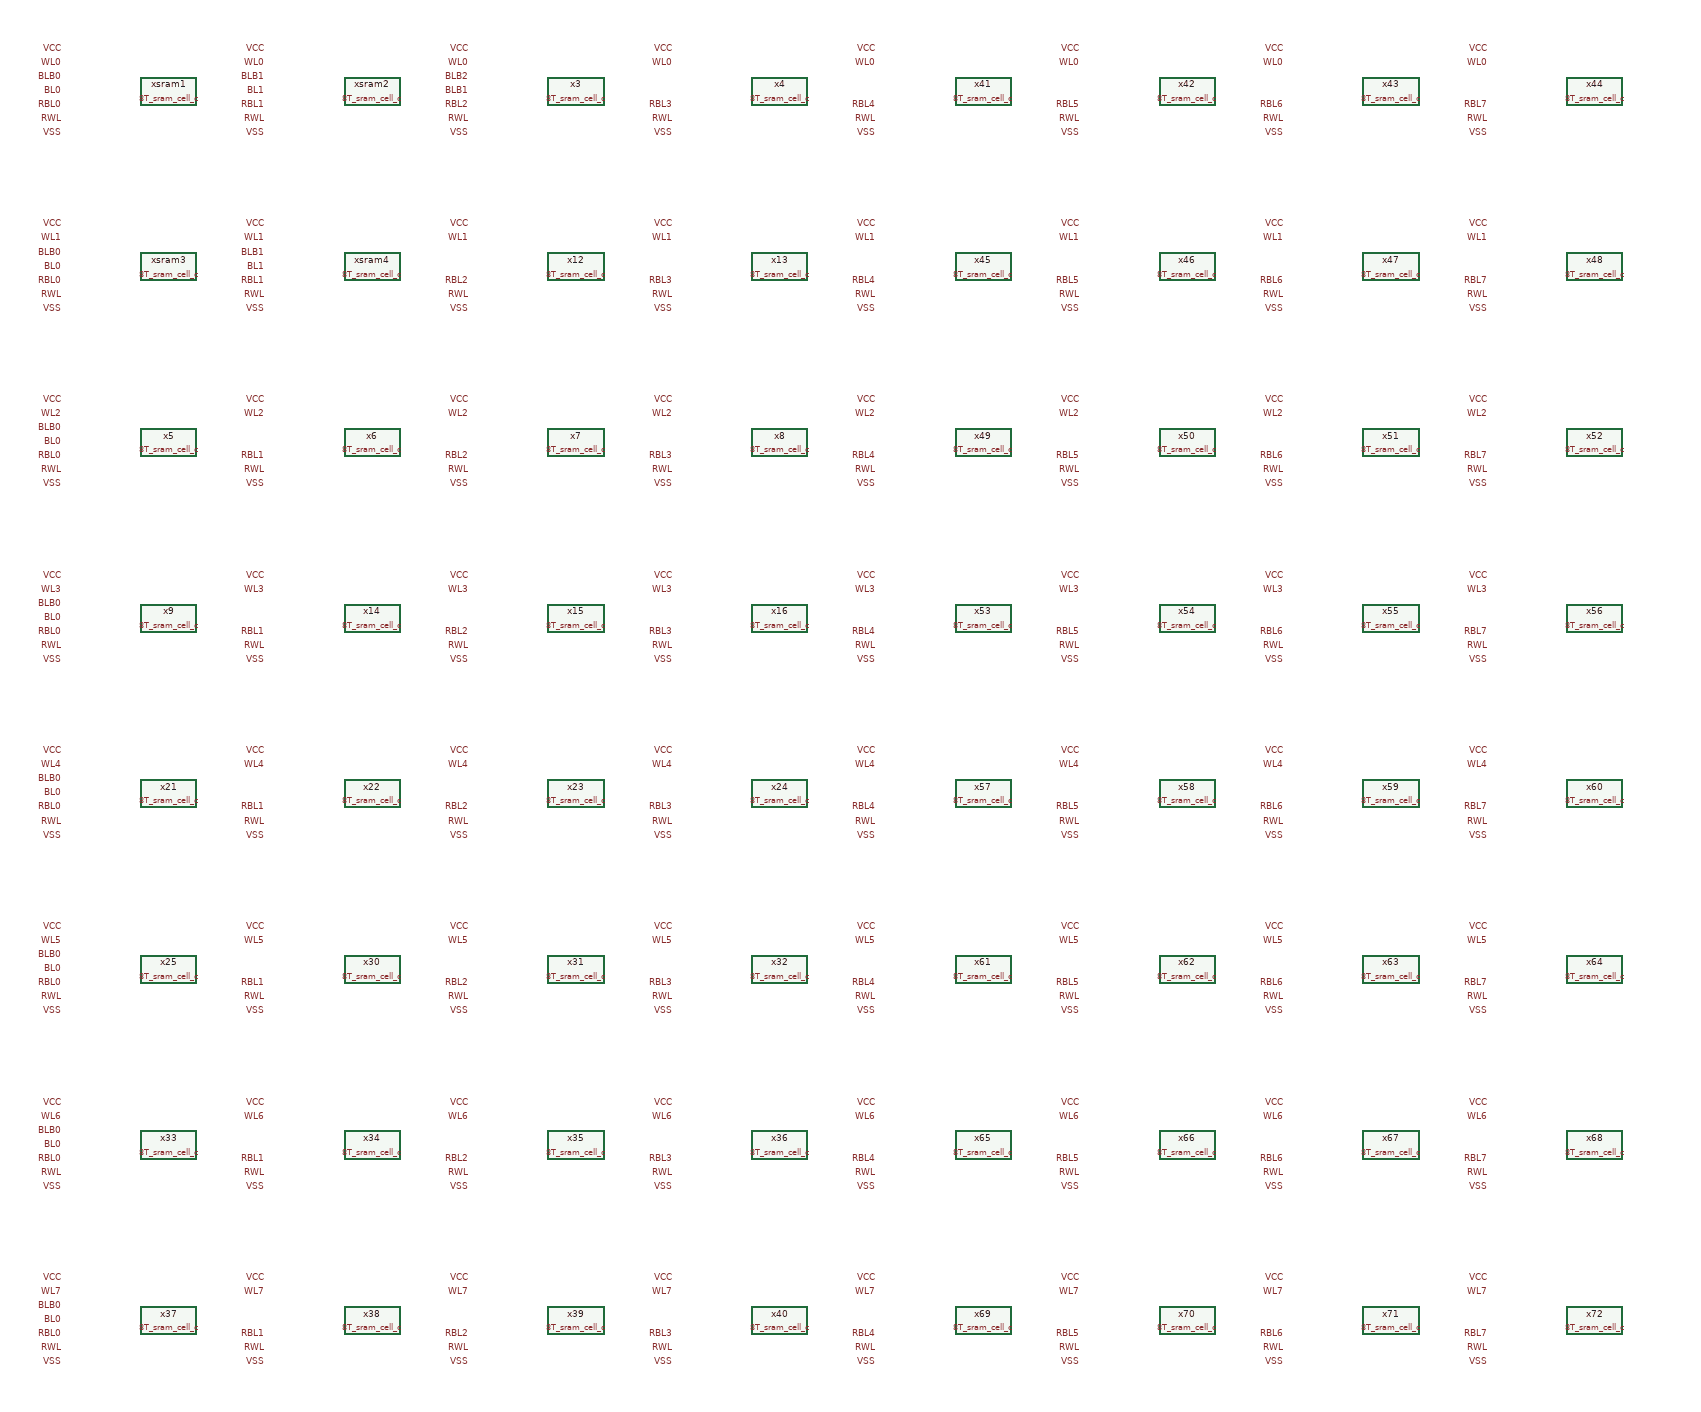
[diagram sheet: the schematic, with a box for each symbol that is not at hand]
v {xschem version=3.4.8RC file_version=1.3}
G {}
K {}
V {}
S {}
F {}
E {}
C {8T_sram_cell_c.sym} 1090 -2060 0 1 {name=xsram1}
C {lab_pin.sym} 940 -2120 0 0 {name=p51 sig_type=std_logic lab=VCC}
C {lab_pin.sym} 940 -2100 0 0 {name=p1 sig_type=std_logic lab=WL0}
C {lab_pin.sym} 940 -2080 0 0 {name=p3 sig_type=std_logic lab=BLB0}
C {lab_pin.sym} 940 -2060 0 0 {name=p4 sig_type=std_logic lab=BL0}
C {lab_pin.sym} 940 -2040 0 0 {name=p112 sig_type=std_logic lab=RBL0}
C {lab_pin.sym} 940 -2020 0 0 {name=p87 sig_type=std_logic lab=RWL}
C {lab_pin.sym} 940 -2000 0 0 {name=p43 sig_type=std_logic lab=VSS}
C {8T_sram_cell_c.sym} 1380 -2060 0 1 {name=xsram2}
C {lab_pin.sym} 1230 -2120 0 0 {name=p6 sig_type=std_logic lab=VCC}
C {lab_pin.sym} 1230 -2100 0 0 {name=p2 sig_type=std_logic lab=WL0}
C {lab_pin.sym} 1230 -2080 0 0 {name=p76 sig_type=std_logic lab=BLB1}
C {lab_pin.sym} 1230 -2060 0 0 {name=p77 sig_type=std_logic lab=BL1}
C {lab_pin.sym} 1230 -2040 0 0 {name=p105 sig_type=std_logic lab=RBL1}
C {lab_pin.sym} 1230 -2020 0 0 {name=p15 sig_type=std_logic lab=RWL}
C {lab_pin.sym} 1230 -2000 0 0 {name=p5 sig_type=std_logic lab=VSS}
C {8T_sram_cell_c.sym} 1090 -1810 0 1 {name=xsram3}
C {lab_pin.sym} 940 -1870 0 0 {name=p62 sig_type=std_logic lab=VCC}
C {lab_pin.sym} 940 -1850 0 0 {name=p107 sig_type=std_logic lab=WL1}
C {lab_pin.sym} 940 -1830 0 0 {name=p7 sig_type=std_logic lab=BLB0}
C {lab_pin.sym} 940 -1810 0 0 {name=p8 sig_type=std_logic lab=BL0}
C {lab_pin.sym} 940 -1790 0 0 {name=p50 sig_type=std_logic lab=RBL0}
C {lab_pin.sym} 940 -1770 0 0 {name=p10 sig_type=std_logic lab=RWL}
C {lab_pin.sym} 940 -1750 0 0 {name=p9 sig_type=std_logic lab=VSS}
C {8T_sram_cell_c.sym} 1380 -1810 0 1 {name=xsram4}
C {lab_pin.sym} 1230 -1870 0 0 {name=p63 sig_type=std_logic lab=VCC}
C {lab_pin.sym} 1230 -1850 0 0 {name=p108 sig_type=std_logic lab=WL1}
C {lab_pin.sym} 1230 -1830 0 0 {name=p80 sig_type=std_logic lab=BLB1}
C {lab_pin.sym} 1230 -1810 0 0 {name=p81 sig_type=std_logic lab=BL1}
C {lab_pin.sym} 1230 -1790 0 0 {name=p46 sig_type=std_logic lab=RBL1}
C {lab_pin.sym} 1230 -1770 0 0 {name=p13 sig_type=std_logic lab=RWL}
C {lab_pin.sym} 1230 -1750 0 0 {name=p12 sig_type=std_logic lab=VSS}


C {lab_pin.sym} 1520 -2100 0 0 {name=p28 sig_type=std_logic lab=WL0}
C {lab_pin.sym} 1520 -2000 0 0 {name=p31 sig_type=std_logic lab=VSS}
C {lab_pin.sym} 1520 -2120 0 0 {name=p32 sig_type=std_logic lab=VCC}
C {lab_pin.sym} 1520 -2020 0 0 {name=p33 sig_type=std_logic lab=RWL}
C {lab_pin.sym} 1810 -2100 0 0 {name=p36 sig_type=std_logic lab=WL0}
C {lab_pin.sym} 1810 -2000 0 0 {name=p39 sig_type=std_logic lab=VSS}
C {lab_pin.sym} 1810 -2120 0 0 {name=p40 sig_type=std_logic lab=VCC}
C {8T_sram_cell_c.sym} 1670 -2060 0 1 {name=x3}
C {lab_pin.sym} 1810 -2020 0 0 {name=p41 sig_type=std_logic lab=RWL}
C {8T_sram_cell_c.sym} 1960 -2060 0 1 {name=x4}
C {lab_pin.sym} 1810 -2040 0 0 {name=p52 sig_type=std_logic lab=RBL3}
C {lab_pin.sym} 1520 -2040 0 0 {name=p88 sig_type=std_logic lab=RBL2}





C {lab_pin.sym} 1520 -1750 0 0 {name=p19 sig_type=std_logic lab=VSS}

C {lab_pin.sym} 1520 -1770 0 0 {name=p20 sig_type=std_logic lab=RWL}
C {lab_pin.sym} 1810 -1750 0 0 {name=p22 sig_type=std_logic lab=VSS}
C {8T_sram_cell_c.sym} 1670 -1810 0 1 {name=x12}
C {lab_pin.sym} 1810 -1770 0 0 {name=p23 sig_type=std_logic lab=RWL}
C {8T_sram_cell_c.sym} 1960 -1810 0 1 {name=x13}


C {lab_pin.sym} 1520 -1870 0 0 {name=p64 sig_type=std_logic lab=VCC}
C {lab_pin.sym} 1810 -1870 0 0 {name=p65 sig_type=std_logic lab=VCC}

C {lab_pin.sym} 1520 -1850 0 0 {name=p113 sig_type=std_logic lab=WL1}
C {lab_pin.sym} 1810 -1850 0 0 {name=p114 sig_type=std_logic lab=WL1}
C {lab_pin.sym} 1810 -1790 0 0 {name=p29 sig_type=std_logic lab=RBL3}
C {lab_pin.sym} 1520 -1790 0 0 {name=p37 sig_type=std_logic lab=RBL2}


C {lab_pin.sym} 940 -1500 0 0 {name=p11 sig_type=std_logic lab=VSS}
C {lab_pin.sym} 940 -1520 0 0 {name=p14 sig_type=std_logic lab=RWL}
C {lab_pin.sym} 1230 -1500 0 0 {name=p16 sig_type=std_logic lab=VSS}
C {8T_sram_cell_c.sym} 1090 -1560 0 1 {name=x5}
C {lab_pin.sym} 1230 -1520 0 0 {name=p21 sig_type=std_logic lab=RWL}
C {lab_pin.sym} 1520 -1500 0 0 {name=p24 sig_type=std_logic lab=VSS}
C {8T_sram_cell_c.sym} 1380 -1560 0 1 {name=x6}
C {lab_pin.sym} 1520 -1520 0 0 {name=p25 sig_type=std_logic lab=RWL}
C {lab_pin.sym} 1810 -1500 0 0 {name=p27 sig_type=std_logic lab=VSS}
C {8T_sram_cell_c.sym} 1670 -1560 0 1 {name=x7}
C {lab_pin.sym} 1810 -1520 0 0 {name=p30 sig_type=std_logic lab=RWL}
C {8T_sram_cell_c.sym} 1960 -1560 0 1 {name=x8}
C {lab_pin.sym} 940 -1620 0 0 {name=p34 sig_type=std_logic lab=VCC}
C {lab_pin.sym} 1230 -1620 0 0 {name=p35 sig_type=std_logic lab=VCC}
C {lab_pin.sym} 1520 -1620 0 0 {name=p38 sig_type=std_logic lab=VCC}
C {lab_pin.sym} 1810 -1620 0 0 {name=p42 sig_type=std_logic lab=VCC}
C {lab_pin.sym} 940 -1600 0 0 {name=p44 sig_type=std_logic lab=WL2}
C {lab_pin.sym} 1230 -1600 0 0 {name=p45 sig_type=std_logic lab=WL2}
C {lab_pin.sym} 1520 -1600 0 0 {name=p47 sig_type=std_logic lab=WL2}
C {lab_pin.sym} 1810 -1600 0 0 {name=p48 sig_type=std_logic lab=WL2}
C {lab_pin.sym} 1810 -1540 0 0 {name=p49 sig_type=std_logic lab=RBL3}
C {lab_pin.sym} 1520 -1540 0 0 {name=p53 sig_type=std_logic lab=RBL2}
C {lab_pin.sym} 1230 -1540 0 0 {name=p54 sig_type=std_logic lab=RBL1}
C {lab_pin.sym} 940 -1540 0 0 {name=p55 sig_type=std_logic lab=RBL0}
C {lab_pin.sym} 940 -1250 0 0 {name=p56 sig_type=std_logic lab=VSS}
C {lab_pin.sym} 940 -1270 0 0 {name=p57 sig_type=std_logic lab=RWL}
C {lab_pin.sym} 1230 -1250 0 0 {name=p58 sig_type=std_logic lab=VSS}
C {8T_sram_cell_c.sym} 1090 -1310 0 1 {name=x9}
C {lab_pin.sym} 1230 -1270 0 0 {name=p61 sig_type=std_logic lab=RWL}
C {lab_pin.sym} 1520 -1250 0 0 {name=p66 sig_type=std_logic lab=VSS}
C {8T_sram_cell_c.sym} 1380 -1310 0 1 {name=x14}
C {lab_pin.sym} 1520 -1270 0 0 {name=p67 sig_type=std_logic lab=RWL}
C {lab_pin.sym} 1810 -1250 0 0 {name=p68 sig_type=std_logic lab=VSS}
C {8T_sram_cell_c.sym} 1670 -1310 0 1 {name=x15}
C {lab_pin.sym} 1810 -1270 0 0 {name=p94 sig_type=std_logic lab=RWL}
C {8T_sram_cell_c.sym} 1960 -1310 0 1 {name=x16}
C {lab_pin.sym} 940 -1370 0 0 {name=p97 sig_type=std_logic lab=VCC}
C {lab_pin.sym} 1230 -1370 0 0 {name=p98 sig_type=std_logic lab=VCC}
C {lab_pin.sym} 1520 -1370 0 0 {name=p100 sig_type=std_logic lab=VCC}
C {lab_pin.sym} 1810 -1370 0 0 {name=p101 sig_type=std_logic lab=VCC}
C {lab_pin.sym} 940 -1350 0 0 {name=p102 sig_type=std_logic lab=WL3}
C {lab_pin.sym} 1230 -1350 0 0 {name=p103 sig_type=std_logic lab=WL3}
C {lab_pin.sym} 1520 -1350 0 0 {name=p104 sig_type=std_logic lab=WL3}
C {lab_pin.sym} 1810 -1350 0 0 {name=p106 sig_type=std_logic lab=WL3}
C {lab_pin.sym} 1810 -1290 0 0 {name=p109 sig_type=std_logic lab=RBL3}
C {lab_pin.sym} 1520 -1290 0 0 {name=p110 sig_type=std_logic lab=RBL2}
C {lab_pin.sym} 1230 -1290 0 0 {name=p111 sig_type=std_logic lab=RBL1}
C {lab_pin.sym} 940 -1290 0 0 {name=p115 sig_type=std_logic lab=RBL0}
C {lab_pin.sym} 940 -1000 0 0 {name=p116 sig_type=std_logic lab=VSS}
C {lab_pin.sym} 940 -1020 0 0 {name=p117 sig_type=std_logic lab=RWL}
C {lab_pin.sym} 1230 -1000 0 0 {name=p118 sig_type=std_logic lab=VSS}
C {8T_sram_cell_c.sym} 1090 -1060 0 1 {name=x21}
C {lab_pin.sym} 1230 -1020 0 0 {name=p120 sig_type=std_logic lab=RWL}
C {lab_pin.sym} 1520 -1000 0 0 {name=p123 sig_type=std_logic lab=VSS}
C {8T_sram_cell_c.sym} 1380 -1060 0 1 {name=x22}
C {lab_pin.sym} 1520 -1020 0 0 {name=p125 sig_type=std_logic lab=RWL}
C {lab_pin.sym} 1810 -1000 0 0 {name=p127 sig_type=std_logic lab=VSS}
C {8T_sram_cell_c.sym} 1670 -1060 0 1 {name=x23}
C {lab_pin.sym} 1810 -1020 0 0 {name=p129 sig_type=std_logic lab=RWL}
C {8T_sram_cell_c.sym} 1960 -1060 0 1 {name=x24}
C {lab_pin.sym} 940 -1120 0 0 {name=p130 sig_type=std_logic lab=VCC}
C {lab_pin.sym} 1230 -1120 0 0 {name=p138 sig_type=std_logic lab=VCC}
C {lab_pin.sym} 1520 -1120 0 0 {name=p147 sig_type=std_logic lab=VCC}
C {lab_pin.sym} 1810 -1120 0 0 {name=p148 sig_type=std_logic lab=VCC}
C {lab_pin.sym} 940 -1100 0 0 {name=p149 sig_type=std_logic lab=WL4}
C {lab_pin.sym} 1230 -1100 0 0 {name=p156 sig_type=std_logic lab=WL4}
C {lab_pin.sym} 1520 -1100 0 0 {name=p157 sig_type=std_logic lab=WL4}
C {lab_pin.sym} 1810 -1100 0 0 {name=p158 sig_type=std_logic lab=WL4}
C {lab_pin.sym} 1810 -1040 0 0 {name=p165 sig_type=std_logic lab=RBL3}
C {lab_pin.sym} 1520 -1040 0 0 {name=p166 sig_type=std_logic lab=RBL2}
C {lab_pin.sym} 1230 -1040 0 0 {name=p167 sig_type=std_logic lab=RBL1}
C {lab_pin.sym} 940 -1040 0 0 {name=p175 sig_type=std_logic lab=RBL0}
C {lab_pin.sym} 940 -750 0 0 {name=p176 sig_type=std_logic lab=VSS}
C {lab_pin.sym} 940 -770 0 0 {name=p177 sig_type=std_logic lab=RWL}
C {lab_pin.sym} 1230 -750 0 0 {name=p178 sig_type=std_logic lab=VSS}
C {8T_sram_cell_c.sym} 1090 -810 0 1 {name=x25}
C {lab_pin.sym} 1230 -770 0 0 {name=p179 sig_type=std_logic lab=RWL}
C {lab_pin.sym} 1520 -750 0 0 {name=p180 sig_type=std_logic lab=VSS}
C {8T_sram_cell_c.sym} 1380 -810 0 1 {name=x30}
C {lab_pin.sym} 1520 -770 0 0 {name=p181 sig_type=std_logic lab=RWL}
C {lab_pin.sym} 1810 -750 0 0 {name=p182 sig_type=std_logic lab=VSS}
C {8T_sram_cell_c.sym} 1670 -810 0 1 {name=x31}
C {lab_pin.sym} 1810 -770 0 0 {name=p184 sig_type=std_logic lab=RWL}
C {8T_sram_cell_c.sym} 1960 -810 0 1 {name=x32}
C {lab_pin.sym} 940 -870 0 0 {name=p185 sig_type=std_logic lab=VCC}
C {lab_pin.sym} 1230 -870 0 0 {name=p186 sig_type=std_logic lab=VCC}
C {lab_pin.sym} 1520 -870 0 0 {name=p187 sig_type=std_logic lab=VCC}
C {lab_pin.sym} 1810 -870 0 0 {name=p188 sig_type=std_logic lab=VCC}
C {lab_pin.sym} 940 -850 0 0 {name=p189 sig_type=std_logic lab=WL5}
C {lab_pin.sym} 1230 -850 0 0 {name=p190 sig_type=std_logic lab=WL5}
C {lab_pin.sym} 1520 -850 0 0 {name=p191 sig_type=std_logic lab=WL5}
C {lab_pin.sym} 1810 -850 0 0 {name=p193 sig_type=std_logic lab=WL5}
C {lab_pin.sym} 1810 -790 0 0 {name=p194 sig_type=std_logic lab=RBL3}
C {lab_pin.sym} 1520 -790 0 0 {name=p195 sig_type=std_logic lab=RBL2}
C {lab_pin.sym} 1230 -790 0 0 {name=p196 sig_type=std_logic lab=RBL1}
C {lab_pin.sym} 940 -790 0 0 {name=p197 sig_type=std_logic lab=RBL0}
C {lab_pin.sym} 940 -500 0 0 {name=p198 sig_type=std_logic lab=VSS}
C {lab_pin.sym} 940 -520 0 0 {name=p199 sig_type=std_logic lab=RWL}
C {lab_pin.sym} 1230 -500 0 0 {name=p200 sig_type=std_logic lab=VSS}
C {8T_sram_cell_c.sym} 1090 -560 0 1 {name=x33}
C {lab_pin.sym} 1230 -520 0 0 {name=p202 sig_type=std_logic lab=RWL}
C {lab_pin.sym} 1520 -500 0 0 {name=p203 sig_type=std_logic lab=VSS}
C {8T_sram_cell_c.sym} 1380 -560 0 1 {name=x34}
C {lab_pin.sym} 1520 -520 0 0 {name=p204 sig_type=std_logic lab=RWL}
C {lab_pin.sym} 1810 -500 0 0 {name=p205 sig_type=std_logic lab=VSS}
C {8T_sram_cell_c.sym} 1670 -560 0 1 {name=x35}
C {lab_pin.sym} 1810 -520 0 0 {name=p206 sig_type=std_logic lab=RWL}
C {8T_sram_cell_c.sym} 1960 -560 0 1 {name=x36}
C {lab_pin.sym} 940 -620 0 0 {name=p207 sig_type=std_logic lab=VCC}
C {lab_pin.sym} 1230 -620 0 0 {name=p208 sig_type=std_logic lab=VCC}
C {lab_pin.sym} 1520 -620 0 0 {name=p209 sig_type=std_logic lab=VCC}
C {lab_pin.sym} 1810 -620 0 0 {name=p222 sig_type=std_logic lab=VCC}
C {lab_pin.sym} 940 -600 0 0 {name=p223 sig_type=std_logic lab=WL6}
C {lab_pin.sym} 1230 -600 0 0 {name=p224 sig_type=std_logic lab=WL6}
C {lab_pin.sym} 1520 -600 0 0 {name=p225 sig_type=std_logic lab=WL6}
C {lab_pin.sym} 1810 -600 0 0 {name=p226 sig_type=std_logic lab=WL6}
C {lab_pin.sym} 1810 -540 0 0 {name=p227 sig_type=std_logic lab=RBL3}
C {lab_pin.sym} 1520 -540 0 0 {name=p228 sig_type=std_logic lab=RBL2}
C {lab_pin.sym} 1230 -540 0 0 {name=p229 sig_type=std_logic lab=RBL1}
C {lab_pin.sym} 940 -540 0 0 {name=p234 sig_type=std_logic lab=RBL0}
C {lab_pin.sym} 940 -250 0 0 {name=p235 sig_type=std_logic lab=VSS}
C {lab_pin.sym} 940 -270 0 0 {name=p236 sig_type=std_logic lab=RWL}
C {lab_pin.sym} 1230 -250 0 0 {name=p237 sig_type=std_logic lab=VSS}
C {8T_sram_cell_c.sym} 1090 -310 0 1 {name=x37}
C {lab_pin.sym} 1230 -270 0 0 {name=p242 sig_type=std_logic lab=RWL}
C {lab_pin.sym} 1520 -250 0 0 {name=p243 sig_type=std_logic lab=VSS}
C {8T_sram_cell_c.sym} 1380 -310 0 1 {name=x38}
C {lab_pin.sym} 1520 -270 0 0 {name=p244 sig_type=std_logic lab=RWL}
C {lab_pin.sym} 1810 -250 0 0 {name=p245 sig_type=std_logic lab=VSS}
C {8T_sram_cell_c.sym} 1670 -310 0 1 {name=x39}
C {lab_pin.sym} 1810 -270 0 0 {name=p246 sig_type=std_logic lab=RWL}
C {8T_sram_cell_c.sym} 1960 -310 0 1 {name=x40}
C {lab_pin.sym} 940 -370 0 0 {name=p247 sig_type=std_logic lab=VCC}
C {lab_pin.sym} 1230 -370 0 0 {name=p248 sig_type=std_logic lab=VCC}
C {lab_pin.sym} 1520 -370 0 0 {name=p249 sig_type=std_logic lab=VCC}
C {lab_pin.sym} 1810 -370 0 0 {name=p258 sig_type=std_logic lab=VCC}
C {lab_pin.sym} 940 -350 0 0 {name=p259 sig_type=std_logic lab=WL7}
C {lab_pin.sym} 1230 -350 0 0 {name=p260 sig_type=std_logic lab=WL7}
C {lab_pin.sym} 1520 -350 0 0 {name=p261 sig_type=std_logic lab=WL7}
C {lab_pin.sym} 1810 -350 0 0 {name=p262 sig_type=std_logic lab=WL7}
C {lab_pin.sym} 1810 -290 0 0 {name=p263 sig_type=std_logic lab=RBL3}
C {lab_pin.sym} 1520 -290 0 0 {name=p264 sig_type=std_logic lab=RBL2}
C {lab_pin.sym} 1230 -290 0 0 {name=p265 sig_type=std_logic lab=RBL1}
C {lab_pin.sym} 940 -290 0 0 {name=p266 sig_type=std_logic lab=RBL0}
C {8T_sram_cell_c.sym} 2250 -2060 0 1 {name=x41}
C {lab_pin.sym} 2970 -2040 0 0 {name=p267 sig_type=std_logic lab=RBL7}
C {lab_pin.sym} 2680 -2040 0 0 {name=p268 sig_type=std_logic lab=RBL6}
C {lab_pin.sym} 2390 -2040 0 0 {name=p269 sig_type=std_logic lab=RBL5}
C {lab_pin.sym} 2100 -2040 0 0 {name=p270 sig_type=std_logic lab=RBL4}
C {lab_pin.sym} 2100 -2100 0 0 {name=p271 sig_type=std_logic lab=WL0}
C {lab_pin.sym} 2100 -2000 0 0 {name=p272 sig_type=std_logic lab=VSS}
C {lab_pin.sym} 2100 -2120 0 0 {name=p273 sig_type=std_logic lab=VCC}
C {lab_pin.sym} 2100 -2020 0 0 {name=p274 sig_type=std_logic lab=RWL}
C {lab_pin.sym} 2390 -2100 0 0 {name=p275 sig_type=std_logic lab=WL0}
C {lab_pin.sym} 2390 -2000 0 0 {name=p276 sig_type=std_logic lab=VSS}
C {lab_pin.sym} 2390 -2120 0 0 {name=p293 sig_type=std_logic lab=VCC}
C {8T_sram_cell_c.sym} 2540 -2060 0 1 {name=x42}
C {lab_pin.sym} 2390 -2020 0 0 {name=p294 sig_type=std_logic lab=RWL}
C {lab_pin.sym} 2680 -2100 0 0 {name=p295 sig_type=std_logic lab=WL0}
C {lab_pin.sym} 2680 -2000 0 0 {name=p296 sig_type=std_logic lab=VSS}
C {lab_pin.sym} 2680 -2120 0 0 {name=p297 sig_type=std_logic lab=VCC}
C {8T_sram_cell_c.sym} 2830 -2060 0 1 {name=x43}
C {lab_pin.sym} 2680 -2020 0 0 {name=p298 sig_type=std_logic lab=RWL}
C {lab_pin.sym} 2970 -2100 0 0 {name=p299 sig_type=std_logic lab=WL0}
C {lab_pin.sym} 2970 -2000 0 0 {name=p300 sig_type=std_logic lab=VSS}
C {lab_pin.sym} 2970 -2120 0 0 {name=p301 sig_type=std_logic lab=VCC}
C {8T_sram_cell_c.sym} 3120 -2060 0 1 {name=x44}
C {lab_pin.sym} 2970 -2020 0 0 {name=p302 sig_type=std_logic lab=RWL}
C {8T_sram_cell_c.sym} 2250 -1810 0 1 {name=x45}
C {lab_pin.sym} 2100 -1750 0 0 {name=p303 sig_type=std_logic lab=VSS}
C {lab_pin.sym} 2100 -1770 0 0 {name=p304 sig_type=std_logic lab=RWL}
C {lab_pin.sym} 2390 -1750 0 0 {name=p305 sig_type=std_logic lab=VSS}
C {8T_sram_cell_c.sym} 2540 -1810 0 1 {name=x46}
C {lab_pin.sym} 2390 -1770 0 0 {name=p306 sig_type=std_logic lab=RWL}
C {lab_pin.sym} 2680 -1750 0 0 {name=p307 sig_type=std_logic lab=VSS}
C {8T_sram_cell_c.sym} 2830 -1810 0 1 {name=x47}
C {lab_pin.sym} 2680 -1770 0 0 {name=p308 sig_type=std_logic lab=RWL}
C {lab_pin.sym} 2970 -1750 0 0 {name=p309 sig_type=std_logic lab=VSS}
C {8T_sram_cell_c.sym} 3120 -1810 0 1 {name=x48}
C {lab_pin.sym} 2970 -1770 0 0 {name=p310 sig_type=std_logic lab=RWL}
C {lab_pin.sym} 2100 -1870 0 0 {name=p311 sig_type=std_logic lab=VCC}
C {lab_pin.sym} 2390 -1870 0 0 {name=p312 sig_type=std_logic lab=VCC}
C {lab_pin.sym} 2680 -1870 0 0 {name=p313 sig_type=std_logic lab=VCC}
C {lab_pin.sym} 2970 -1870 0 0 {name=p314 sig_type=std_logic lab=VCC}
C {lab_pin.sym} 2100 -1850 0 0 {name=p315 sig_type=std_logic lab=WL1}
C {lab_pin.sym} 2390 -1850 0 0 {name=p316 sig_type=std_logic lab=WL1}
C {lab_pin.sym} 2680 -1850 0 0 {name=p317 sig_type=std_logic lab=WL1}
C {lab_pin.sym} 2970 -1850 0 0 {name=p318 sig_type=std_logic lab=WL1}
C {lab_pin.sym} 2970 -1790 0 0 {name=p319 sig_type=std_logic lab=RBL7}
C {lab_pin.sym} 2680 -1790 0 0 {name=p320 sig_type=std_logic lab=RBL6}
C {lab_pin.sym} 2390 -1790 0 0 {name=p321 sig_type=std_logic lab=RBL5}
C {lab_pin.sym} 2100 -1790 0 0 {name=p322 sig_type=std_logic lab=RBL4}
C {8T_sram_cell_c.sym} 2250 -1560 0 1 {name=x49}
C {lab_pin.sym} 2100 -1500 0 0 {name=p323 sig_type=std_logic lab=VSS}
C {lab_pin.sym} 2100 -1520 0 0 {name=p324 sig_type=std_logic lab=RWL}
C {lab_pin.sym} 2390 -1500 0 0 {name=p325 sig_type=std_logic lab=VSS}
C {8T_sram_cell_c.sym} 2540 -1560 0 1 {name=x50}
C {lab_pin.sym} 2390 -1520 0 0 {name=p326 sig_type=std_logic lab=RWL}
C {lab_pin.sym} 2680 -1500 0 0 {name=p327 sig_type=std_logic lab=VSS}
C {8T_sram_cell_c.sym} 2830 -1560 0 1 {name=x51}
C {lab_pin.sym} 2680 -1520 0 0 {name=p328 sig_type=std_logic lab=RWL}
C {lab_pin.sym} 2970 -1500 0 0 {name=p329 sig_type=std_logic lab=VSS}
C {8T_sram_cell_c.sym} 3120 -1560 0 1 {name=x52}
C {lab_pin.sym} 2970 -1520 0 0 {name=p330 sig_type=std_logic lab=RWL}
C {lab_pin.sym} 2100 -1620 0 0 {name=p331 sig_type=std_logic lab=VCC}
C {lab_pin.sym} 2390 -1620 0 0 {name=p332 sig_type=std_logic lab=VCC}
C {lab_pin.sym} 2680 -1620 0 0 {name=p333 sig_type=std_logic lab=VCC}
C {lab_pin.sym} 2970 -1620 0 0 {name=p334 sig_type=std_logic lab=VCC}
C {lab_pin.sym} 2100 -1600 0 0 {name=p335 sig_type=std_logic lab=WL2}
C {lab_pin.sym} 2390 -1600 0 0 {name=p336 sig_type=std_logic lab=WL2}
C {lab_pin.sym} 2680 -1600 0 0 {name=p337 sig_type=std_logic lab=WL2}
C {lab_pin.sym} 2970 -1600 0 0 {name=p338 sig_type=std_logic lab=WL2}
C {lab_pin.sym} 2970 -1540 0 0 {name=p339 sig_type=std_logic lab=RBL7}
C {lab_pin.sym} 2680 -1540 0 0 {name=p340 sig_type=std_logic lab=RBL6}
C {lab_pin.sym} 2390 -1540 0 0 {name=p341 sig_type=std_logic lab=RBL5}
C {lab_pin.sym} 2100 -1540 0 0 {name=p342 sig_type=std_logic lab=RBL4}
C {8T_sram_cell_c.sym} 2250 -1310 0 1 {name=x53}
C {lab_pin.sym} 2100 -1250 0 0 {name=p343 sig_type=std_logic lab=VSS}
C {lab_pin.sym} 2100 -1270 0 0 {name=p344 sig_type=std_logic lab=RWL}
C {lab_pin.sym} 2390 -1250 0 0 {name=p345 sig_type=std_logic lab=VSS}
C {8T_sram_cell_c.sym} 2540 -1310 0 1 {name=x54}
C {lab_pin.sym} 2390 -1270 0 0 {name=p346 sig_type=std_logic lab=RWL}
C {lab_pin.sym} 2680 -1250 0 0 {name=p347 sig_type=std_logic lab=VSS}
C {8T_sram_cell_c.sym} 2830 -1310 0 1 {name=x55}
C {lab_pin.sym} 2680 -1270 0 0 {name=p348 sig_type=std_logic lab=RWL}
C {lab_pin.sym} 2970 -1250 0 0 {name=p349 sig_type=std_logic lab=VSS}
C {8T_sram_cell_c.sym} 3120 -1310 0 1 {name=x56}
C {lab_pin.sym} 2970 -1270 0 0 {name=p350 sig_type=std_logic lab=RWL}
C {lab_pin.sym} 2100 -1370 0 0 {name=p351 sig_type=std_logic lab=VCC}
C {lab_pin.sym} 2390 -1370 0 0 {name=p352 sig_type=std_logic lab=VCC}
C {lab_pin.sym} 2680 -1370 0 0 {name=p353 sig_type=std_logic lab=VCC}
C {lab_pin.sym} 2970 -1370 0 0 {name=p354 sig_type=std_logic lab=VCC}
C {lab_pin.sym} 2100 -1350 0 0 {name=p355 sig_type=std_logic lab=WL3}
C {lab_pin.sym} 2390 -1350 0 0 {name=p356 sig_type=std_logic lab=WL3}
C {lab_pin.sym} 2680 -1350 0 0 {name=p357 sig_type=std_logic lab=WL3}
C {lab_pin.sym} 2970 -1350 0 0 {name=p358 sig_type=std_logic lab=WL3}
C {lab_pin.sym} 2970 -1290 0 0 {name=p359 sig_type=std_logic lab=RBL7}
C {lab_pin.sym} 2680 -1290 0 0 {name=p360 sig_type=std_logic lab=RBL6}
C {lab_pin.sym} 2390 -1290 0 0 {name=p361 sig_type=std_logic lab=RBL5}
C {lab_pin.sym} 2100 -1290 0 0 {name=p362 sig_type=std_logic lab=RBL4}
C {8T_sram_cell_c.sym} 2250 -1060 0 1 {name=x57}
C {lab_pin.sym} 2100 -1000 0 0 {name=p363 sig_type=std_logic lab=VSS}
C {lab_pin.sym} 2100 -1020 0 0 {name=p364 sig_type=std_logic lab=RWL}
C {lab_pin.sym} 2390 -1000 0 0 {name=p365 sig_type=std_logic lab=VSS}
C {8T_sram_cell_c.sym} 2540 -1060 0 1 {name=x58}
C {lab_pin.sym} 2390 -1020 0 0 {name=p366 sig_type=std_logic lab=RWL}
C {lab_pin.sym} 2680 -1000 0 0 {name=p367 sig_type=std_logic lab=VSS}
C {8T_sram_cell_c.sym} 2830 -1060 0 1 {name=x59}
C {lab_pin.sym} 2680 -1020 0 0 {name=p368 sig_type=std_logic lab=RWL}
C {lab_pin.sym} 2970 -1000 0 0 {name=p369 sig_type=std_logic lab=VSS}
C {8T_sram_cell_c.sym} 3120 -1060 0 1 {name=x60}
C {lab_pin.sym} 2970 -1020 0 0 {name=p370 sig_type=std_logic lab=RWL}
C {lab_pin.sym} 2100 -1120 0 0 {name=p371 sig_type=std_logic lab=VCC}
C {lab_pin.sym} 2390 -1120 0 0 {name=p372 sig_type=std_logic lab=VCC}
C {lab_pin.sym} 2680 -1120 0 0 {name=p373 sig_type=std_logic lab=VCC}
C {lab_pin.sym} 2970 -1120 0 0 {name=p374 sig_type=std_logic lab=VCC}
C {lab_pin.sym} 2100 -1100 0 0 {name=p375 sig_type=std_logic lab=WL4}
C {lab_pin.sym} 2390 -1100 0 0 {name=p376 sig_type=std_logic lab=WL4}
C {lab_pin.sym} 2680 -1100 0 0 {name=p377 sig_type=std_logic lab=WL4}
C {lab_pin.sym} 2970 -1100 0 0 {name=p378 sig_type=std_logic lab=WL4}
C {lab_pin.sym} 2970 -1040 0 0 {name=p379 sig_type=std_logic lab=RBL7}
C {lab_pin.sym} 2680 -1040 0 0 {name=p380 sig_type=std_logic lab=RBL6}
C {lab_pin.sym} 2390 -1040 0 0 {name=p381 sig_type=std_logic lab=RBL5}
C {lab_pin.sym} 2100 -1040 0 0 {name=p382 sig_type=std_logic lab=RBL4}
C {8T_sram_cell_c.sym} 2250 -810 0 1 {name=x61}
C {lab_pin.sym} 2100 -750 0 0 {name=p383 sig_type=std_logic lab=VSS}
C {lab_pin.sym} 2100 -770 0 0 {name=p384 sig_type=std_logic lab=RWL}
C {lab_pin.sym} 2390 -750 0 0 {name=p385 sig_type=std_logic lab=VSS}
C {8T_sram_cell_c.sym} 2540 -810 0 1 {name=x62}
C {lab_pin.sym} 2390 -770 0 0 {name=p386 sig_type=std_logic lab=RWL}
C {lab_pin.sym} 2680 -750 0 0 {name=p387 sig_type=std_logic lab=VSS}
C {8T_sram_cell_c.sym} 2830 -810 0 1 {name=x63}
C {lab_pin.sym} 2680 -770 0 0 {name=p388 sig_type=std_logic lab=RWL}
C {lab_pin.sym} 2970 -750 0 0 {name=p389 sig_type=std_logic lab=VSS}
C {8T_sram_cell_c.sym} 3120 -810 0 1 {name=x64}
C {lab_pin.sym} 2970 -770 0 0 {name=p390 sig_type=std_logic lab=RWL}
C {lab_pin.sym} 2100 -870 0 0 {name=p391 sig_type=std_logic lab=VCC}
C {lab_pin.sym} 2390 -870 0 0 {name=p392 sig_type=std_logic lab=VCC}
C {lab_pin.sym} 2680 -870 0 0 {name=p393 sig_type=std_logic lab=VCC}
C {lab_pin.sym} 2970 -870 0 0 {name=p394 sig_type=std_logic lab=VCC}
C {lab_pin.sym} 2100 -850 0 0 {name=p395 sig_type=std_logic lab=WL5}
C {lab_pin.sym} 2390 -850 0 0 {name=p396 sig_type=std_logic lab=WL5}
C {lab_pin.sym} 2680 -850 0 0 {name=p397 sig_type=std_logic lab=WL5}
C {lab_pin.sym} 2970 -850 0 0 {name=p398 sig_type=std_logic lab=WL5}
C {lab_pin.sym} 2970 -790 0 0 {name=p399 sig_type=std_logic lab=RBL7}
C {lab_pin.sym} 2680 -790 0 0 {name=p400 sig_type=std_logic lab=RBL6}
C {lab_pin.sym} 2390 -790 0 0 {name=p401 sig_type=std_logic lab=RBL5}
C {lab_pin.sym} 2100 -790 0 0 {name=p402 sig_type=std_logic lab=RBL4}
C {8T_sram_cell_c.sym} 2250 -560 0 1 {name=x65}
C {lab_pin.sym} 2100 -500 0 0 {name=p403 sig_type=std_logic lab=VSS}
C {lab_pin.sym} 2100 -520 0 0 {name=p404 sig_type=std_logic lab=RWL}
C {lab_pin.sym} 2390 -500 0 0 {name=p405 sig_type=std_logic lab=VSS}
C {8T_sram_cell_c.sym} 2540 -560 0 1 {name=x66}
C {lab_pin.sym} 2390 -520 0 0 {name=p406 sig_type=std_logic lab=RWL}
C {lab_pin.sym} 2680 -500 0 0 {name=p407 sig_type=std_logic lab=VSS}
C {8T_sram_cell_c.sym} 2830 -560 0 1 {name=x67}
C {lab_pin.sym} 2680 -520 0 0 {name=p408 sig_type=std_logic lab=RWL}
C {lab_pin.sym} 2970 -500 0 0 {name=p409 sig_type=std_logic lab=VSS}
C {8T_sram_cell_c.sym} 3120 -560 0 1 {name=x68}
C {lab_pin.sym} 2970 -520 0 0 {name=p410 sig_type=std_logic lab=RWL}
C {lab_pin.sym} 2100 -620 0 0 {name=p411 sig_type=std_logic lab=VCC}
C {lab_pin.sym} 2390 -620 0 0 {name=p412 sig_type=std_logic lab=VCC}
C {lab_pin.sym} 2680 -620 0 0 {name=p413 sig_type=std_logic lab=VCC}
C {lab_pin.sym} 2970 -620 0 0 {name=p414 sig_type=std_logic lab=VCC}
C {lab_pin.sym} 2100 -600 0 0 {name=p415 sig_type=std_logic lab=WL6}
C {lab_pin.sym} 2390 -600 0 0 {name=p416 sig_type=std_logic lab=WL6}
C {lab_pin.sym} 2680 -600 0 0 {name=p417 sig_type=std_logic lab=WL6}
C {lab_pin.sym} 2970 -600 0 0 {name=p418 sig_type=std_logic lab=WL6}
C {lab_pin.sym} 2970 -540 0 0 {name=p419 sig_type=std_logic lab=RBL7}
C {lab_pin.sym} 2680 -540 0 0 {name=p420 sig_type=std_logic lab=RBL6}
C {lab_pin.sym} 2390 -540 0 0 {name=p421 sig_type=std_logic lab=RBL5}
C {lab_pin.sym} 2100 -540 0 0 {name=p422 sig_type=std_logic lab=RBL4}
C {8T_sram_cell_c.sym} 2250 -310 0 1 {name=x69}
C {lab_pin.sym} 2100 -250 0 0 {name=p423 sig_type=std_logic lab=VSS}
C {lab_pin.sym} 2100 -270 0 0 {name=p424 sig_type=std_logic lab=RWL}
C {lab_pin.sym} 2390 -250 0 0 {name=p425 sig_type=std_logic lab=VSS}
C {8T_sram_cell_c.sym} 2540 -310 0 1 {name=x70}
C {lab_pin.sym} 2390 -270 0 0 {name=p426 sig_type=std_logic lab=RWL}
C {lab_pin.sym} 2680 -250 0 0 {name=p427 sig_type=std_logic lab=VSS}
C {8T_sram_cell_c.sym} 2830 -310 0 1 {name=x71}
C {lab_pin.sym} 2680 -270 0 0 {name=p428 sig_type=std_logic lab=RWL}
C {lab_pin.sym} 2970 -250 0 0 {name=p429 sig_type=std_logic lab=VSS}
C {8T_sram_cell_c.sym} 3120 -310 0 1 {name=x72}
C {lab_pin.sym} 2970 -270 0 0 {name=p430 sig_type=std_logic lab=RWL}
C {lab_pin.sym} 2100 -370 0 0 {name=p431 sig_type=std_logic lab=VCC}
C {lab_pin.sym} 2390 -370 0 0 {name=p432 sig_type=std_logic lab=VCC}
C {lab_pin.sym} 2680 -370 0 0 {name=p433 sig_type=std_logic lab=VCC}
C {lab_pin.sym} 2970 -370 0 0 {name=p434 sig_type=std_logic lab=VCC}
C {lab_pin.sym} 2100 -350 0 0 {name=p435 sig_type=std_logic lab=WL7}
C {lab_pin.sym} 2390 -350 0 0 {name=p436 sig_type=std_logic lab=WL7}
C {lab_pin.sym} 2680 -350 0 0 {name=p437 sig_type=std_logic lab=WL7}
C {lab_pin.sym} 2970 -350 0 0 {name=p438 sig_type=std_logic lab=WL7}
C {lab_pin.sym} 2970 -290 0 0 {name=p439 sig_type=std_logic lab=RBL7}
C {lab_pin.sym} 2680 -290 0 0 {name=p440 sig_type=std_logic lab=RBL6}
C {lab_pin.sym} 2390 -290 0 0 {name=p441 sig_type=std_logic lab=RBL5}
C {lab_pin.sym} 2100 -290 0 0 {name=p442 sig_type=std_logic lab=RBL4}


C {lab_pin.sym} 940 -1580 0 0 {name=p17 sig_type=std_logic lab=BLB0}
C {lab_pin.sym} 940 -1560 0 0 {name=p18 sig_type=std_logic lab=BL0}
C {lab_pin.sym} 940 -1330 0 0 {name=p26 sig_type=std_logic lab=BLB0}
C {lab_pin.sym} 940 -1310 0 0 {name=p59 sig_type=std_logic lab=BL0}
C {lab_pin.sym} 940 -1080 0 0 {name=p60 sig_type=std_logic lab=BLB0}
C {lab_pin.sym} 940 -1060 0 0 {name=p69 sig_type=std_logic lab=BL0}
C {lab_pin.sym} 940 -830 0 0 {name=p70 sig_type=std_logic lab=BLB0}
C {lab_pin.sym} 940 -810 0 0 {name=p71 sig_type=std_logic lab=BL0}
C {lab_pin.sym} 940 -580 0 0 {name=p72 sig_type=std_logic lab=BLB0}
C {lab_pin.sym} 940 -560 0 0 {name=p73 sig_type=std_logic lab=BL0}
C {lab_pin.sym} 940 -330 0 0 {name=p74 sig_type=std_logic lab=BLB0}
C {lab_pin.sym} 940 -310 0 0 {name=p75 sig_type=std_logic lab=BL0}

C {lab_pin.sym} 1520 -2080 0 0 {name=p78 sig_type=std_logic lab=BLB2}
C {lab_pin.sym} 1520 -2060 0 0 {name=p79 sig_type=std_logic lab=BLB1}

